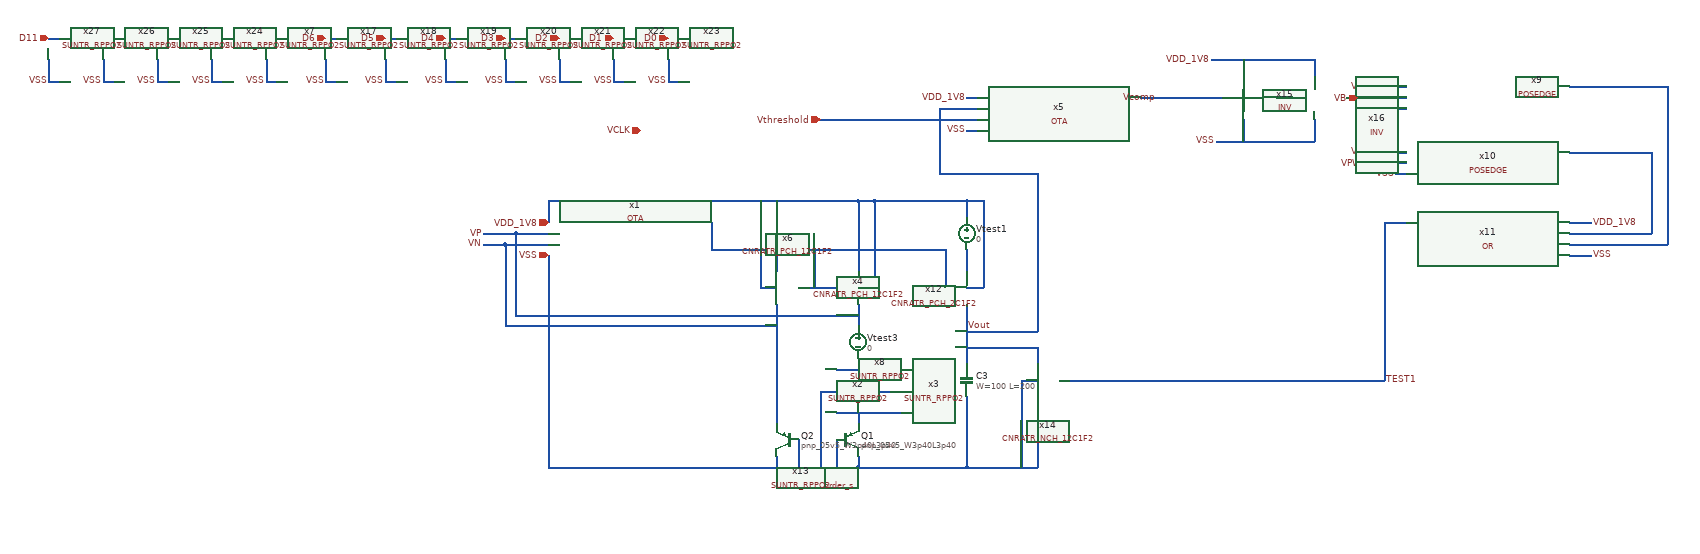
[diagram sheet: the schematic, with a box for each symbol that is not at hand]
v {xschem version=3.4.4 file_version=1.2
}
G {}
K {}
V {}
S {}
E {}
N 410 -110 410 -90 {
lab=VSS}
N 260 -110 260 -90 {
lab=VSS}
N 300 -140 300 -90 {
lab=VSS}
N 370 -140 370 -90 {
lab=VSS}
N 260 -260 260 -170 {
lab=VN}
N 260 -310 260 -260 {
lab=VN}
N 300 -420 370 -420 {
lab=#net1}
N 410 -530 410 -450 {
lab=VDD_1V8}
N 260 -530 260 -450 {
lab=VDD_1V8}
N 260 -390 260 -310 {
lab=VN}
N -160 -580 -160 -540 {
lab=VDD_1V8}
N 410 -580 410 -530 {
lab=VDD_1V8}
N 260 -580 260 -530 {
lab=VDD_1V8}
N -160 -480 -160 -90 {
lab=VSS}
N -240 -500 -240 -350 {
lab=VN}
N 410 -390 410 -350 {
lab=VP}
N 230 -420 260 -420 {
lab=VDD_1V8}
N 230 -580 230 -420 {
lab=VDD_1V8}
N 410 -420 440 -420 {
lab=VDD_1V8}
N 440 -580 440 -420 {
lab=VDD_1V8}
N 410 -580 440 -580 {
lab=VDD_1V8}
N 410 -290 410 -270 {
lab=#net2}
N 410 -190 410 -170 {
lab=#net3}
N 340 -230 340 -90 {
lab=VSS}
N 140 -540 140 -490 {
lab=#net1}
N 330 -490 330 -420 {
lab=#net1}
N 330 -490 570 -490 {
lab=#net1}
N 570 -490 570 -420 {
lab=#net1}
N 440 -580 610 -580 {
lab=VDD_1V8}
N 610 -420 640 -420 {
lab=VDD_1V8}
N 640 -580 640 -420 {
lab=VDD_1V8}
N 610 -580 640 -580 {
lab=VDD_1V8}
N 410 -90 610 -90 {
lab=VSS}
N 610 -390 610 -280 {
lab=Vout}
N 610 -310 740 -310 {
lab=Vout}
N 740 -310 740 -280 {
lab=Vout}
N 740 -220 740 -90 {
lab=VSS}
N 610 -90 740 -90 {
lab=VSS}
N 710 -250 740 -250 {
lab=VSS}
N 710 -250 710 -90 {
lab=VSS}
N 610 -220 610 -90 {
lab=VSS}
N 560 -720 560 -630 {
lab=Vout}
N 560 -630 740 -630 {
lab=Vout}
N 740 -630 740 -340 {
lab=Vout}
N 610 -340 740 -340 {
lab=Vout}
N 560 -750 560 -720 {
lab=Vout}
N 560 -750 630 -750 {
lab=Vout}
N 590 -730 630 -730 {
lab=Vthreshold}
N 340 -730 590 -730 {
lab=Vthreshold}
N 610 -490 610 -450 {
lab=#net4}
N 610 -580 610 -550 {
lab=VDD_1V8}
N 1400 -750 1420 -750 {
lab=VSS}
N 1400 -790 1420 -790 {
lab=VDD_1V8}
N 1400 -630 1420 -630 {
lab=VSS}
N 1400 -670 1420 -670 {
lab=VDD_1V8}
N 1400 -650 1420 -650 {
lab=VPWR_UP}
N 1180 -770 1210 -770 {
lab=#net5}
N 1070 -690 1250 -690 {
lab=VSS}
N 1250 -730 1250 -690 {
lab=VSS}
N 1120 -730 1120 -690 {
lab=VSS}
N 1060 -840 1250 -840 {
lab=VDD_1V8}
N 1250 -840 1250 -810 {
lab=VDD_1V8}
N 1120 -840 1120 -810 {
lab=VDD_1V8}
N 930 -770 1080 -770 {
lab=Vcomp}
N 1310 -770 1420 -770 {
lab=VB}
N 1720 -540 1760 -540 {
lab=VDD_1V8}
N 1720 -480 1760 -480 {
lab=VSS}
N 1720 -670 1870 -670 {
lab=#net6}
N 1870 -670 1870 -520 {
lab=#net6}
N 1720 -520 1870 -520 {
lab=#net6}
N 1720 -790 1900 -790 {
lab=#net7}
N 1900 -790 1900 -500 {
lab=#net7}
N 1720 -500 1900 -500 {
lab=#net7}
N 780 -250 1380 -250 {
lab=TEST1}
N 1380 -540 1380 -250 {
lab=TEST1}
N 1380 -540 1420 -540 {
lab=TEST1}
N 610 -770 630 -770 {
lab=VDD_1V8}
N 610 -710 630 -710 {
lab=VSS}
N 140 -490 330 -490 {
lab=#net1}
N 140 -580 410 -580 {
lab=VDD_1V8}
N 140 -370 410 -370 {
lab=VP}
N 140 -350 260 -350 {
lab=VN}
N 140 -90 410 -90 {
lab=VSS}
N -160 -90 140 -90 {
lab=VSS}
N -240 -350 140 -350 {
lab=VN}
N -220 -370 140 -370 {
lab=VP}
N -220 -520 -220 -370 {
lab=VP}
N -160 -580 140 -580 {
lab=VDD_1V8}
N -220 -520 -160 -520 {
lab=VP}
N -240 -500 -160 -500 {
lab=VN}
N -280 -520 -220 -520 {
lab=VP}
N -280 -500 -240 -500 {
lab=VN}
N 340 -230 470 -230 {
lab=VSS}
N 370 -270 490 -270 {
lab=#net2}
N 370 -190 490 -190 {
lab=#net3}
N -680 -880 -660 -880 {
lab=D7}
N -680 -840 -680 -800 {
lab=VSS}
N -680 -800 -660 -800 {
lab=VSS}
N -570 -880 -550 -880 {
lab=D6}
N -570 -840 -570 -800 {
lab=VSS}
N -570 -800 -550 -800 {
lab=VSS}
N -460 -880 -440 -880 {
lab=D5}
N -460 -840 -460 -800 {
lab=VSS}
N -460 -800 -440 -800 {
lab=VSS}
N -350 -880 -330 -880 {
lab=D4}
N -350 -840 -350 -800 {
lab=VSS}
N -350 -800 -330 -800 {
lab=VSS}
N -240 -880 -220 -880 {
lab=D3}
N -240 -840 -240 -800 {
lab=VSS}
N -240 -800 -220 -800 {
lab=VSS}
N -140 -880 -120 -880 {
lab=D2}
N -140 -840 -140 -800 {
lab=VSS}
N -140 -800 -120 -800 {
lab=VSS}
N -40 -880 -20 -880 {
lab=D1}
N -40 -840 -40 -800 {
lab=VSS}
N -40 -800 -20 -800 {
lab=VSS}
N 60 -880 80 -880 {
lab=D0}
N 60 -840 60 -800 {
lab=VSS}
N 60 -800 80 -800 {
lab=VSS}
N -780 -880 -760 -880 {
lab=D8}
N -780 -840 -780 -800 {
lab=VSS}
N -780 -800 -760 -800 {
lab=VSS}
N -880 -880 -860 -880 {
lab=D9}
N -880 -840 -880 -800 {
lab=VSS}
N -880 -800 -860 -800 {
lab=VSS}
N -980 -880 -960 -880 {
lab=D10}
N -980 -840 -980 -800 {
lab=VSS}
N -980 -800 -960 -800 {
lab=VSS}
N -1080 -880 -1060 -880 {
lab=D7}
N -1080 -840 -1080 -800 {
lab=VSS}
N -1080 -800 -1060 -800 {
lab=VSS}
C {cborder/border_s.sym} 520 0 0 0 {
user="aam"
company="wulff"}
C {devices/ipin.sym} -160 -480 0 0 {name=p2 lab=VSS}
C {devices/ipin.sym} -160 -540 0 0 {name=p1 lab=VDD_1V8}
C {sky130_fd_pr/pnp_05v5.sym} 390 -140 0 0 {name=Q1
model=pnp_05v5_W3p40L3p40
m=2
spiceprefix=X
}
C {sky130_fd_pr/pnp_05v5.sym} 280 -140 0 1 {name=Q2
model=pnp_05v5_W3p40L3p40
m=1
spiceprefix=X
}
C {devices/vsource.sym} 410 -320 0 0 {name=Vtest3 value=0 savecurrent=false}
C {SUN_TR_SKY130NM/SUNTR_RPPO2.sym} 410 -270 1 0 {name=x2 }
C {SUN_TR_SKY130NM/SUNTR_RPPO2.sym} 490 -270 1 0 {name=x3 }
C {CNR_GR05_SKY130NM/OTA.sym} -10 -510 0 0 {name=x1}
C {sky130_fd_pr/cap_mim_m3_2.sym} 610 -250 0 0 {name=C3 model=cap_mim_m3_2 W=100 L=200 MF=2 spiceprefix=X}
C {devices/lab_pin.sym} 610 -350 0 1 {name=p5 sig_type=std_logic lab=Vout}
C {devices/ipin.sym} 1400 -650 0 0 {name=p6 lab=VPWR_UP}
C {CNR_GR05_SKY130NM/OTA.sym} 780 -740 0 0 {name=x5}
C {devices/ipin.sym} 340 -730 0 0 {name=p7 lab=Vthreshold}
C {devices/lab_pin.sym} 960 -770 1 1 {name=p8 sig_type=std_logic lab=Vcomp}
C {devices/vsource.sym} 610 -520 0 0 {name=Vtest1 value=0 savecurrent=false}
C {CNR_GR05_SKY130NM/POSEDGE.sym} 1570 -770 0 0 {name=x9}
C {devices/lab_pin.sym} 1400 -790 0 0 {name=p9 sig_type=std_logic lab=VDD_1V8}
C {devices/lab_pin.sym} 1400 -750 0 0 {name=p10 sig_type=std_logic lab=VSS}
C {CNR_GR05_SKY130NM/POSEDGE.sym} 1570 -650 0 0 {name=x10}
C {devices/lab_pin.sym} 1400 -670 0 0 {name=p11 sig_type=std_logic lab=VDD_1V8}
C {devices/lab_pin.sym} 1400 -630 0 0 {name=p12 sig_type=std_logic lab=VSS}
C {CNR_GR05_SKY130NM/OR.sym} 1570 -510 0 1 {name=x11}
C {devices/lab_pin.sym} 1760 -480 0 1 {name=p13 sig_type=std_logic lab=VSS}
C {devices/lab_pin.sym} 1760 -540 0 1 {name=p14 sig_type=std_logic lab=VDD_1V8}
C {devices/lab_pin.sym} 1380 -250 0 1 {name=p15 sig_type=std_logic lab=TEST1}
C {CNR_ATR_SKY130NM/CNRATR_PCH_2C1F2.sym} 570 -420 0 0 {name=x12 }
C {CNR_ATR_SKY130NM/CNRATR_PCH_12C1F2.sym} 370 -420 0 0 {name=x4 }
C {CNR_ATR_SKY130NM/CNRATR_PCH_12C1F2.sym} 300 -420 0 1 {name=x6 }
C {SUN_TR_SKY130NM/SUNTR_RPPO2.sym} 450 -270 1 0 {name=x8 }
C {SUN_TR_SKY130NM/SUNTR_RPPO2.sym} 370 -270 1 0 {name=x13 }
C {CNR_ATR_SKY130NM/CNRATR_NCH_12C1F2.sym} 780 -250 0 1 {name=x14 }
C {CNR_GR05_SKY130NM/INV.sym} 1230 -770 0 0 {name=x15}
C {CNR_GR05_SKY130NM/INV.sym} 1360 -770 0 0 {name=x16}
C {devices/lab_pin.sym} 1060 -840 0 0 {name=p21 sig_type=std_logic lab=VDD_1V8}
C {devices/lab_pin.sym} 1070 -690 0 0 {name=p22 sig_type=std_logic lab=VSS}
C {devices/lab_pin.sym} 610 -710 0 0 {name=p16 sig_type=std_logic lab=VSS}
C {devices/lab_pin.sym} 610 -770 0 0 {name=p17 sig_type=std_logic lab=VDD_1V8}
C {devices/lab_pin.sym} -280 -520 0 0 {name=p3 sig_type=std_logic lab=VP}
C {devices/lab_pin.sym} -280 -500 0 0 {name=p4 sig_type=std_logic lab=VN}
C {devices/ipin.sym} 10 -710 0 0 {name=p20 lab=VCLK}
C {devices/ipin.sym} 1330 -770 3 0 {name=p25 lab=VB}
C {devices/ipin.sym} -680 -880 0 0 {name=p18 lab=D7}
C {SUN_TR_SKY130NM/SUNTR_RPPO2.sym} -660 -880 1 0 {name=x7 }
C {devices/lab_pin.sym} -680 -800 0 0 {name=p19 sig_type=std_logic lab=VSS}
C {devices/ipin.sym} -570 -880 0 0 {name=p23 lab=D6}
C {SUN_TR_SKY130NM/SUNTR_RPPO2.sym} -550 -880 1 0 {name=x17 }
C {devices/lab_pin.sym} -570 -800 0 0 {name=p24 sig_type=std_logic lab=VSS}
C {devices/ipin.sym} -460 -880 0 0 {name=p26 lab=D5}
C {SUN_TR_SKY130NM/SUNTR_RPPO2.sym} -440 -880 1 0 {name=x18 }
C {devices/lab_pin.sym} -460 -800 0 0 {name=p27 sig_type=std_logic lab=VSS}
C {devices/ipin.sym} -350 -880 0 0 {name=p28 lab=D4}
C {SUN_TR_SKY130NM/SUNTR_RPPO2.sym} -330 -880 1 0 {name=x19 }
C {devices/lab_pin.sym} -350 -800 0 0 {name=p29 sig_type=std_logic lab=VSS}
C {devices/ipin.sym} -240 -880 0 0 {name=p30 lab=D3}
C {SUN_TR_SKY130NM/SUNTR_RPPO2.sym} -220 -880 1 0 {name=x20 }
C {devices/lab_pin.sym} -240 -800 0 0 {name=p31 sig_type=std_logic lab=VSS}
C {devices/ipin.sym} -140 -880 0 0 {name=p32 lab=D2}
C {SUN_TR_SKY130NM/SUNTR_RPPO2.sym} -120 -880 1 0 {name=x21 }
C {devices/lab_pin.sym} -140 -800 0 0 {name=p33 sig_type=std_logic lab=VSS}
C {devices/ipin.sym} -40 -880 0 0 {name=p34 lab=D1}
C {SUN_TR_SKY130NM/SUNTR_RPPO2.sym} -20 -880 1 0 {name=x22 }
C {devices/lab_pin.sym} -40 -800 0 0 {name=p35 sig_type=std_logic lab=VSS}
C {devices/ipin.sym} 60 -880 0 0 {name=p36 lab=D0}
C {SUN_TR_SKY130NM/SUNTR_RPPO2.sym} 80 -880 1 0 {name=x23 }
C {devices/lab_pin.sym} 60 -800 0 0 {name=p37 sig_type=std_logic lab=VSS}
C {devices/ipin.sym} -780 -880 0 0 {name=p38 lab=D8}
C {SUN_TR_SKY130NM/SUNTR_RPPO2.sym} -760 -880 1 0 {name=x24 }
C {devices/lab_pin.sym} -780 -800 0 0 {name=p39 sig_type=std_logic lab=VSS}
C {devices/ipin.sym} -880 -880 0 0 {name=p40 lab=D9
}
C {SUN_TR_SKY130NM/SUNTR_RPPO2.sym} -860 -880 1 0 {name=x25 }
C {devices/lab_pin.sym} -880 -800 0 0 {name=p41 sig_type=std_logic lab=VSS}
C {devices/ipin.sym} -980 -880 0 0 {name=p42 lab=D10}
C {SUN_TR_SKY130NM/SUNTR_RPPO2.sym} -960 -880 1 0 {name=x26 }
C {devices/lab_pin.sym} -980 -800 0 0 {name=p43 sig_type=std_logic lab=VSS}
C {devices/ipin.sym} -1080 -880 0 0 {name=p44 lab=D11}
C {SUN_TR_SKY130NM/SUNTR_RPPO2.sym} -1060 -880 1 0 {name=x27 }
C {devices/lab_pin.sym} -1080 -800 0 0 {name=p45 sig_type=std_logic lab=VSS}
